VERSION 5.8 ;
BUSBITCHARS "[]" ;
DIVIDERCHAR "/" ;
UNITS
    DATABASE MICRONS 1000 ;
END UNITS

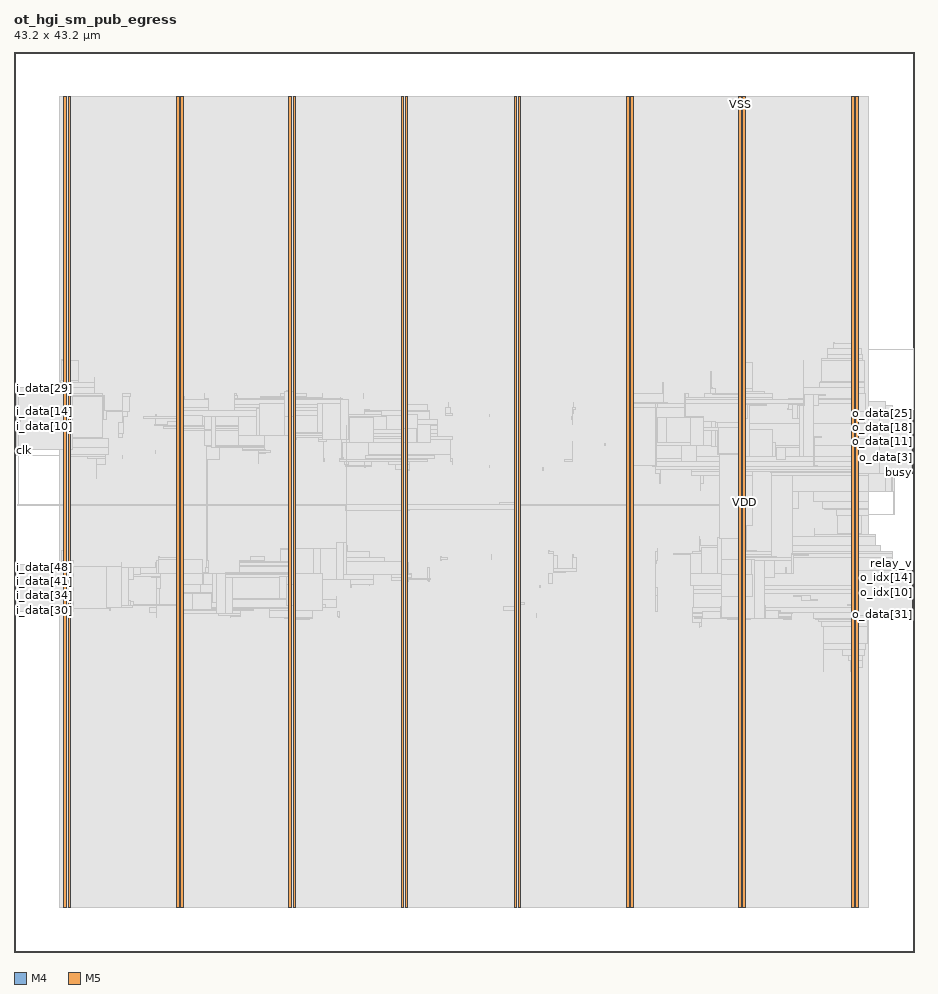
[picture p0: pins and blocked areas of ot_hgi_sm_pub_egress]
MACRO ot_hgi_sm_pub_egress
  FOREIGN ot_hgi_sm_pub_egress 0 0 ;
  CLASS BLOCK ;
  SIZE 43.2 BY 43.2 ;
  PIN busy
    DIRECTION OUTPUT ;
    USE SIGNAL ;
    PORT
      LAYER M4 ;
        RECT  43.116 22.992 43.2 23.016 ;
    END
  END busy
  PIN clk
    DIRECTION INPUT ;
    USE SIGNAL ;
    PORT
      LAYER M4 ;
        RECT  0 24.048 0.084 24.072 ;
    END
  END clk
  PIN i_busy
    DIRECTION INPUT ;
    USE SIGNAL ;
    PORT
      LAYER M4 ;
        RECT  0 24.144 0.084 24.168 ;
    END
  END i_busy
  PIN i_data[0]
    DIRECTION INPUT ;
    USE SIGNAL ;
    PORT
      LAYER M4 ;
        RECT  0 24.24 0.084 24.264 ;
    END
  END i_data[0]
  PIN i_data[10]
    DIRECTION INPUT ;
    USE SIGNAL ;
    PORT
      LAYER M4 ;
        RECT  0 25.2 0.084 25.224 ;
    END
  END i_data[10]
  PIN i_data[11]
    DIRECTION INPUT ;
    USE SIGNAL ;
    PORT
      LAYER M4 ;
        RECT  0 25.296 0.084 25.32 ;
    END
  END i_data[11]
  PIN i_data[12]
    DIRECTION INPUT ;
    USE SIGNAL ;
    PORT
      LAYER M4 ;
        RECT  0 25.392 0.084 25.416 ;
    END
  END i_data[12]
  PIN i_data[13]
    DIRECTION INPUT ;
    USE SIGNAL ;
    PORT
      LAYER M4 ;
        RECT  0 25.488 0.084 25.512 ;
    END
  END i_data[13]
  PIN i_data[14]
    DIRECTION INPUT ;
    USE SIGNAL ;
    PORT
      LAYER M4 ;
        RECT  0 25.584 0.084 25.608 ;
    END
  END i_data[14]
  PIN i_data[15]
    DIRECTION INPUT ;
    USE SIGNAL ;
    PORT
      LAYER M4 ;
        RECT  0 25.68 0.084 25.704 ;
    END
  END i_data[15]
  PIN i_data[16]
    DIRECTION INPUT ;
    USE SIGNAL ;
    PORT
      LAYER M4 ;
        RECT  0 25.776 0.084 25.8 ;
    END
  END i_data[16]
  PIN i_data[17]
    DIRECTION INPUT ;
    USE SIGNAL ;
    PORT
      LAYER M4 ;
        RECT  0 25.872 0.084 25.896 ;
    END
  END i_data[17]
  PIN i_data[18]
    DIRECTION INPUT ;
    USE SIGNAL ;
    PORT
      LAYER M4 ;
        RECT  0 25.968 0.084 25.992 ;
    END
  END i_data[18]
  PIN i_data[19]
    DIRECTION INPUT ;
    USE SIGNAL ;
    PORT
      LAYER M4 ;
        RECT  0 26.064 0.084 26.088 ;
    END
  END i_data[19]
  PIN i_data[1]
    DIRECTION INPUT ;
    USE SIGNAL ;
    PORT
      LAYER M4 ;
        RECT  0 24.336 0.084 24.36 ;
    END
  END i_data[1]
  PIN i_data[20]
    DIRECTION INPUT ;
    USE SIGNAL ;
    PORT
      LAYER M4 ;
        RECT  0 26.16 0.084 26.184 ;
    END
  END i_data[20]
  PIN i_data[21]
    DIRECTION INPUT ;
    USE SIGNAL ;
    PORT
      LAYER M4 ;
        RECT  0 26.256 0.084 26.28 ;
    END
  END i_data[21]
  PIN i_data[22]
    DIRECTION INPUT ;
    USE SIGNAL ;
    PORT
      LAYER M4 ;
        RECT  0 26.352 0.084 26.376 ;
    END
  END i_data[22]
  PIN i_data[23]
    DIRECTION INPUT ;
    USE SIGNAL ;
    PORT
      LAYER M4 ;
        RECT  0 26.448 0.084 26.472 ;
    END
  END i_data[23]
  PIN i_data[24]
    DIRECTION INPUT ;
    USE SIGNAL ;
    PORT
      LAYER M4 ;
        RECT  0 26.544 0.084 26.568 ;
    END
  END i_data[24]
  PIN i_data[25]
    DIRECTION INPUT ;
    USE SIGNAL ;
    PORT
      LAYER M4 ;
        RECT  0 26.64 0.084 26.664 ;
    END
  END i_data[25]
  PIN i_data[26]
    DIRECTION INPUT ;
    USE SIGNAL ;
    PORT
      LAYER M4 ;
        RECT  0 26.736 0.084 26.76 ;
    END
  END i_data[26]
  PIN i_data[27]
    DIRECTION INPUT ;
    USE SIGNAL ;
    PORT
      LAYER M4 ;
        RECT  0 26.832 0.084 26.856 ;
    END
  END i_data[27]
  PIN i_data[28]
    DIRECTION INPUT ;
    USE SIGNAL ;
    PORT
      LAYER M4 ;
        RECT  0 26.928 0.084 26.952 ;
    END
  END i_data[28]
  PIN i_data[29]
    DIRECTION INPUT ;
    USE SIGNAL ;
    PORT
      LAYER M4 ;
        RECT  0 27.024 0.084 27.048 ;
    END
  END i_data[29]
  PIN i_data[2]
    DIRECTION INPUT ;
    USE SIGNAL ;
    PORT
      LAYER M4 ;
        RECT  0 24.432 0.084 24.456 ;
    END
  END i_data[2]
  PIN i_data[30]
    DIRECTION INPUT ;
    USE SIGNAL ;
    PORT
      LAYER M4 ;
        RECT  0 16.368 0.084 16.392 ;
    END
  END i_data[30]
  PIN i_data[31]
    DIRECTION INPUT ;
    USE SIGNAL ;
    PORT
      LAYER M4 ;
        RECT  0 16.464 0.084 16.488 ;
    END
  END i_data[31]
  PIN i_data[32]
    DIRECTION INPUT ;
    USE SIGNAL ;
    PORT
      LAYER M4 ;
        RECT  0 16.56 0.084 16.584 ;
    END
  END i_data[32]
  PIN i_data[33]
    DIRECTION INPUT ;
    USE SIGNAL ;
    PORT
      LAYER M4 ;
        RECT  0 16.656 0.084 16.68 ;
    END
  END i_data[33]
  PIN i_data[34]
    DIRECTION INPUT ;
    USE SIGNAL ;
    PORT
      LAYER M4 ;
        RECT  0 16.752 0.084 16.776 ;
    END
  END i_data[34]
  PIN i_data[35]
    DIRECTION INPUT ;
    USE SIGNAL ;
    PORT
      LAYER M4 ;
        RECT  0 16.848 0.084 16.872 ;
    END
  END i_data[35]
  PIN i_data[36]
    DIRECTION INPUT ;
    USE SIGNAL ;
    PORT
      LAYER M4 ;
        RECT  0 16.944 0.084 16.968 ;
    END
  END i_data[36]
  PIN i_data[37]
    DIRECTION INPUT ;
    USE SIGNAL ;
    PORT
      LAYER M4 ;
        RECT  0 17.04 0.084 17.064 ;
    END
  END i_data[37]
  PIN i_data[38]
    DIRECTION INPUT ;
    USE SIGNAL ;
    PORT
      LAYER M4 ;
        RECT  0 17.136 0.084 17.16 ;
    END
  END i_data[38]
  PIN i_data[39]
    DIRECTION INPUT ;
    USE SIGNAL ;
    PORT
      LAYER M4 ;
        RECT  0 17.232 0.084 17.256 ;
    END
  END i_data[39]
  PIN i_data[3]
    DIRECTION INPUT ;
    USE SIGNAL ;
    PORT
      LAYER M4 ;
        RECT  0 24.528 0.084 24.552 ;
    END
  END i_data[3]
  PIN i_data[40]
    DIRECTION INPUT ;
    USE SIGNAL ;
    PORT
      LAYER M4 ;
        RECT  0 17.328 0.084 17.352 ;
    END
  END i_data[40]
  PIN i_data[41]
    DIRECTION INPUT ;
    USE SIGNAL ;
    PORT
      LAYER M4 ;
        RECT  0 17.424 0.084 17.448 ;
    END
  END i_data[41]
  PIN i_data[42]
    DIRECTION INPUT ;
    USE SIGNAL ;
    PORT
      LAYER M4 ;
        RECT  0 17.52 0.084 17.544 ;
    END
  END i_data[42]
  PIN i_data[43]
    DIRECTION INPUT ;
    USE SIGNAL ;
    PORT
      LAYER M4 ;
        RECT  0 17.616 0.084 17.64 ;
    END
  END i_data[43]
  PIN i_data[44]
    DIRECTION INPUT ;
    USE SIGNAL ;
    PORT
      LAYER M4 ;
        RECT  0 17.712 0.084 17.736 ;
    END
  END i_data[44]
  PIN i_data[45]
    DIRECTION INPUT ;
    USE SIGNAL ;
    PORT
      LAYER M4 ;
        RECT  0 17.808 0.084 17.832 ;
    END
  END i_data[45]
  PIN i_data[46]
    DIRECTION INPUT ;
    USE SIGNAL ;
    PORT
      LAYER M4 ;
        RECT  0 17.904 0.084 17.928 ;
    END
  END i_data[46]
  PIN i_data[47]
    DIRECTION INPUT ;
    USE SIGNAL ;
    PORT
      LAYER M4 ;
        RECT  0 18 0.084 18.024 ;
    END
  END i_data[47]
  PIN i_data[48]
    DIRECTION INPUT ;
    USE SIGNAL ;
    PORT
      LAYER M4 ;
        RECT  0 18.096 0.084 18.12 ;
    END
  END i_data[48]
  PIN i_data[49]
    DIRECTION INPUT ;
    USE SIGNAL ;
    PORT
      LAYER M4 ;
        RECT  0 18.192 0.084 18.216 ;
    END
  END i_data[49]
  PIN i_data[4]
    DIRECTION INPUT ;
    USE SIGNAL ;
    PORT
      LAYER M4 ;
        RECT  0 24.624 0.084 24.648 ;
    END
  END i_data[4]
  PIN i_data[50]
    DIRECTION INPUT ;
    USE SIGNAL ;
    PORT
      LAYER M4 ;
        RECT  0 18.288 0.084 18.312 ;
    END
  END i_data[50]
  PIN i_data[51]
    DIRECTION INPUT ;
    USE SIGNAL ;
    PORT
      LAYER M4 ;
        RECT  0 18.384 0.084 18.408 ;
    END
  END i_data[51]
  PIN i_data[5]
    DIRECTION INPUT ;
    USE SIGNAL ;
    PORT
      LAYER M4 ;
        RECT  0 24.72 0.084 24.744 ;
    END
  END i_data[5]
  PIN i_data[6]
    DIRECTION INPUT ;
    USE SIGNAL ;
    PORT
      LAYER M4 ;
        RECT  0 24.816 0.084 24.84 ;
    END
  END i_data[6]
  PIN i_data[7]
    DIRECTION INPUT ;
    USE SIGNAL ;
    PORT
      LAYER M4 ;
        RECT  0 24.912 0.084 24.936 ;
    END
  END i_data[7]
  PIN i_data[8]
    DIRECTION INPUT ;
    USE SIGNAL ;
    PORT
      LAYER M4 ;
        RECT  0 25.008 0.084 25.032 ;
    END
  END i_data[8]
  PIN i_data[9]
    DIRECTION INPUT ;
    USE SIGNAL ;
    PORT
      LAYER M4 ;
        RECT  0 25.104 0.084 25.128 ;
    END
  END i_data[9]
  PIN i_v
    DIRECTION INPUT ;
    USE SIGNAL ;
    PORT
      LAYER M4 ;
        RECT  0 18.48 0.084 18.504 ;
    END
  END i_v
  PIN o_data[0]
    DIRECTION OUTPUT ;
    USE SIGNAL ;
    PORT
      LAYER M4 ;
        RECT  43.116 23.088 43.2 23.112 ;
    END
  END o_data[0]
  PIN o_data[10]
    DIRECTION OUTPUT ;
    USE SIGNAL ;
    PORT
      LAYER M4 ;
        RECT  43.116 24.048 43.2 24.072 ;
    END
  END o_data[10]
  PIN o_data[11]
    DIRECTION OUTPUT ;
    USE SIGNAL ;
    PORT
      LAYER M4 ;
        RECT  43.116 24.144 43.2 24.168 ;
    END
  END o_data[11]
  PIN o_data[12]
    DIRECTION OUTPUT ;
    USE SIGNAL ;
    PORT
      LAYER M4 ;
        RECT  43.116 24.24 43.2 24.264 ;
    END
  END o_data[12]
  PIN o_data[13]
    DIRECTION OUTPUT ;
    USE SIGNAL ;
    PORT
      LAYER M4 ;
        RECT  43.116 24.336 43.2 24.36 ;
    END
  END o_data[13]
  PIN o_data[14]
    DIRECTION OUTPUT ;
    USE SIGNAL ;
    PORT
      LAYER M4 ;
        RECT  43.116 24.432 43.2 24.456 ;
    END
  END o_data[14]
  PIN o_data[15]
    DIRECTION OUTPUT ;
    USE SIGNAL ;
    PORT
      LAYER M4 ;
        RECT  43.116 24.528 43.2 24.552 ;
    END
  END o_data[15]
  PIN o_data[16]
    DIRECTION OUTPUT ;
    USE SIGNAL ;
    PORT
      LAYER M4 ;
        RECT  43.116 24.624 43.2 24.648 ;
    END
  END o_data[16]
  PIN o_data[17]
    DIRECTION OUTPUT ;
    USE SIGNAL ;
    PORT
      LAYER M4 ;
        RECT  43.116 24.72 43.2 24.744 ;
    END
  END o_data[17]
  PIN o_data[18]
    DIRECTION OUTPUT ;
    USE SIGNAL ;
    PORT
      LAYER M4 ;
        RECT  43.116 24.816 43.2 24.84 ;
    END
  END o_data[18]
  PIN o_data[19]
    DIRECTION OUTPUT ;
    USE SIGNAL ;
    PORT
      LAYER M4 ;
        RECT  43.116 24.912 43.2 24.936 ;
    END
  END o_data[19]
  PIN o_data[1]
    DIRECTION OUTPUT ;
    USE SIGNAL ;
    PORT
      LAYER M4 ;
        RECT  43.116 23.184 43.2 23.208 ;
    END
  END o_data[1]
  PIN o_data[20]
    DIRECTION OUTPUT ;
    USE SIGNAL ;
    PORT
      LAYER M4 ;
        RECT  43.116 25.008 43.2 25.032 ;
    END
  END o_data[20]
  PIN o_data[21]
    DIRECTION OUTPUT ;
    USE SIGNAL ;
    PORT
      LAYER M4 ;
        RECT  43.116 25.104 43.2 25.128 ;
    END
  END o_data[21]
  PIN o_data[22]
    DIRECTION OUTPUT ;
    USE SIGNAL ;
    PORT
      LAYER M4 ;
        RECT  43.116 25.2 43.2 25.224 ;
    END
  END o_data[22]
  PIN o_data[23]
    DIRECTION OUTPUT ;
    USE SIGNAL ;
    PORT
      LAYER M4 ;
        RECT  43.116 25.296 43.2 25.32 ;
    END
  END o_data[23]
  PIN o_data[24]
    DIRECTION OUTPUT ;
    USE SIGNAL ;
    PORT
      LAYER M4 ;
        RECT  43.116 25.392 43.2 25.416 ;
    END
  END o_data[24]
  PIN o_data[25]
    DIRECTION OUTPUT ;
    USE SIGNAL ;
    PORT
      LAYER M4 ;
        RECT  43.116 25.488 43.2 25.512 ;
    END
  END o_data[25]
  PIN o_data[26]
    DIRECTION OUTPUT ;
    USE SIGNAL ;
    PORT
      LAYER M4 ;
        RECT  43.116 25.584 43.2 25.608 ;
    END
  END o_data[26]
  PIN o_data[27]
    DIRECTION OUTPUT ;
    USE SIGNAL ;
    PORT
      LAYER M4 ;
        RECT  43.116 25.68 43.2 25.704 ;
    END
  END o_data[27]
  PIN o_data[28]
    DIRECTION OUTPUT ;
    USE SIGNAL ;
    PORT
      LAYER M4 ;
        RECT  43.116 25.776 43.2 25.8 ;
    END
  END o_data[28]
  PIN o_data[29]
    DIRECTION OUTPUT ;
    USE SIGNAL ;
    PORT
      LAYER M4 ;
        RECT  43.116 25.872 43.2 25.896 ;
    END
  END o_data[29]
  PIN o_data[2]
    DIRECTION OUTPUT ;
    USE SIGNAL ;
    PORT
      LAYER M4 ;
        RECT  43.116 23.28 43.2 23.304 ;
    END
  END o_data[2]
  PIN o_data[30]
    DIRECTION OUTPUT ;
    USE SIGNAL ;
    PORT
      LAYER M4 ;
        RECT  43.116 25.968 43.2 25.992 ;
    END
  END o_data[30]
  PIN o_data[31]
    DIRECTION OUTPUT ;
    USE SIGNAL ;
    PORT
      LAYER M4 ;
        RECT  43.116 16.176 43.2 16.2 ;
    END
  END o_data[31]
  PIN o_data[3]
    DIRECTION OUTPUT ;
    USE SIGNAL ;
    PORT
      LAYER M4 ;
        RECT  43.116 23.376 43.2 23.4 ;
    END
  END o_data[3]
  PIN o_data[4]
    DIRECTION OUTPUT ;
    USE SIGNAL ;
    PORT
      LAYER M4 ;
        RECT  43.116 23.472 43.2 23.496 ;
    END
  END o_data[4]
  PIN o_data[5]
    DIRECTION OUTPUT ;
    USE SIGNAL ;
    PORT
      LAYER M4 ;
        RECT  43.116 23.568 43.2 23.592 ;
    END
  END o_data[5]
  PIN o_data[6]
    DIRECTION OUTPUT ;
    USE SIGNAL ;
    PORT
      LAYER M4 ;
        RECT  43.116 23.664 43.2 23.688 ;
    END
  END o_data[6]
  PIN o_data[7]
    DIRECTION OUTPUT ;
    USE SIGNAL ;
    PORT
      LAYER M4 ;
        RECT  43.116 23.76 43.2 23.784 ;
    END
  END o_data[7]
  PIN o_data[8]
    DIRECTION OUTPUT ;
    USE SIGNAL ;
    PORT
      LAYER M4 ;
        RECT  43.116 23.856 43.2 23.88 ;
    END
  END o_data[8]
  PIN o_data[9]
    DIRECTION OUTPUT ;
    USE SIGNAL ;
    PORT
      LAYER M4 ;
        RECT  43.116 23.952 43.2 23.976 ;
    END
  END o_data[9]
  PIN o_idx[0]
    DIRECTION OUTPUT ;
    USE SIGNAL ;
    PORT
      LAYER M4 ;
        RECT  43.116 16.272 43.2 16.296 ;
    END
  END o_idx[0]
  PIN o_idx[10]
    DIRECTION OUTPUT ;
    USE SIGNAL ;
    PORT
      LAYER M4 ;
        RECT  43.116 17.232 43.2 17.256 ;
    END
  END o_idx[10]
  PIN o_idx[11]
    DIRECTION OUTPUT ;
    USE SIGNAL ;
    PORT
      LAYER M4 ;
        RECT  43.116 17.328 43.2 17.352 ;
    END
  END o_idx[11]
  PIN o_idx[12]
    DIRECTION OUTPUT ;
    USE SIGNAL ;
    PORT
      LAYER M4 ;
        RECT  43.116 17.424 43.2 17.448 ;
    END
  END o_idx[12]
  PIN o_idx[13]
    DIRECTION OUTPUT ;
    USE SIGNAL ;
    PORT
      LAYER M4 ;
        RECT  43.116 17.52 43.2 17.544 ;
    END
  END o_idx[13]
  PIN o_idx[14]
    DIRECTION OUTPUT ;
    USE SIGNAL ;
    PORT
      LAYER M4 ;
        RECT  43.116 17.616 43.2 17.64 ;
    END
  END o_idx[14]
  PIN o_idx[15]
    DIRECTION OUTPUT ;
    USE SIGNAL ;
    PORT
      LAYER M4 ;
        RECT  43.116 17.712 43.2 17.736 ;
    END
  END o_idx[15]
  PIN o_idx[16]
    DIRECTION OUTPUT ;
    USE SIGNAL ;
    PORT
      LAYER M4 ;
        RECT  43.116 17.808 43.2 17.832 ;
    END
  END o_idx[16]
  PIN o_idx[17]
    DIRECTION OUTPUT ;
    USE SIGNAL ;
    PORT
      LAYER M4 ;
        RECT  43.116 17.904 43.2 17.928 ;
    END
  END o_idx[17]
  PIN o_idx[18]
    DIRECTION OUTPUT ;
    USE SIGNAL ;
    PORT
      LAYER M4 ;
        RECT  43.116 18 43.2 18.024 ;
    END
  END o_idx[18]
  PIN o_idx[19]
    DIRECTION OUTPUT ;
    USE SIGNAL ;
    PORT
      LAYER M4 ;
        RECT  43.116 18.096 43.2 18.12 ;
    END
  END o_idx[19]
  PIN o_idx[1]
    DIRECTION OUTPUT ;
    USE SIGNAL ;
    PORT
      LAYER M4 ;
        RECT  43.116 16.368 43.2 16.392 ;
    END
  END o_idx[1]
  PIN o_idx[2]
    DIRECTION OUTPUT ;
    USE SIGNAL ;
    PORT
      LAYER M4 ;
        RECT  43.116 16.464 43.2 16.488 ;
    END
  END o_idx[2]
  PIN o_idx[3]
    DIRECTION OUTPUT ;
    USE SIGNAL ;
    PORT
      LAYER M4 ;
        RECT  43.116 16.56 43.2 16.584 ;
    END
  END o_idx[3]
  PIN o_idx[4]
    DIRECTION OUTPUT ;
    USE SIGNAL ;
    PORT
      LAYER M4 ;
        RECT  43.116 16.656 43.2 16.68 ;
    END
  END o_idx[4]
  PIN o_idx[5]
    DIRECTION OUTPUT ;
    USE SIGNAL ;
    PORT
      LAYER M4 ;
        RECT  43.116 16.752 43.2 16.776 ;
    END
  END o_idx[5]
  PIN o_idx[6]
    DIRECTION OUTPUT ;
    USE SIGNAL ;
    PORT
      LAYER M4 ;
        RECT  43.116 16.848 43.2 16.872 ;
    END
  END o_idx[6]
  PIN o_idx[7]
    DIRECTION OUTPUT ;
    USE SIGNAL ;
    PORT
      LAYER M4 ;
        RECT  43.116 16.944 43.2 16.968 ;
    END
  END o_idx[7]
  PIN o_idx[8]
    DIRECTION OUTPUT ;
    USE SIGNAL ;
    PORT
      LAYER M4 ;
        RECT  43.116 17.04 43.2 17.064 ;
    END
  END o_idx[8]
  PIN o_idx[9]
    DIRECTION OUTPUT ;
    USE SIGNAL ;
    PORT
      LAYER M4 ;
        RECT  43.116 17.136 43.2 17.16 ;
    END
  END o_idx[9]
  PIN o_v
    DIRECTION OUTPUT ;
    USE SIGNAL ;
    PORT
      LAYER M4 ;
        RECT  43.116 18.192 43.2 18.216 ;
    END
  END o_v
  PIN relay_v
    DIRECTION OUTPUT ;
    USE SIGNAL ;
    PORT
      LAYER M4 ;
        RECT  43.116 18.288 43.2 18.312 ;
    END
  END relay_v
  PIN rn
    DIRECTION INPUT ;
    USE SIGNAL ;
    PORT
      LAYER M4 ;
        RECT  0 18.576 0.084 18.6 ;
    END
  END rn
  PIN VDD
    DIRECTION INOUT ;
    USE POWER ;
    PORT
      LAYER M5 ;
        RECT  40.392 2.151 40.512 41.049 ;
        RECT  34.992 2.151 35.112 41.049 ;
        RECT  29.592 2.151 29.712 41.049 ;
        RECT  24.192 2.151 24.312 41.049 ;
        RECT  18.792 2.151 18.912 41.049 ;
        RECT  13.392 2.151 13.512 41.049 ;
        RECT  7.992 2.151 8.112 41.049 ;
        RECT  2.592 2.151 2.712 41.049 ;
    END
  END VDD
  PIN VSS
    DIRECTION INOUT ;
    USE GROUND ;
    PORT
      LAYER M5 ;
        RECT  40.2 2.137 40.32 41.063 ;
        RECT  34.8 2.137 34.92 41.063 ;
        RECT  29.4 2.137 29.52 41.063 ;
        RECT  24 2.137 24.12 41.063 ;
        RECT  18.6 2.137 18.72 41.063 ;
        RECT  13.2 2.137 13.32 41.063 ;
        RECT  7.8 2.137 7.92 41.063 ;
        RECT  2.4 2.137 2.52 41.063 ;
    END
  END VSS
  # OT_OBS_CLOSED layer=M5 d_um=1.536 added=6
  OBS
    LAYER RVTN ;
     RECT  2.16 2.16 41.04 2.295 ;
     RECT  2.16 2.565 41.04 2.835 ;
     RECT  2.16 3.105 41.04 3.375 ;
     RECT  2.16 3.645 41.04 3.915 ;
     RECT  2.16 4.185 41.04 4.455 ;
     RECT  2.16 4.725 41.04 4.995 ;
     RECT  2.16 5.265 41.04 5.535 ;
     RECT  2.16 5.805 41.04 6.075 ;
     RECT  2.16 6.345 41.04 6.615 ;
     RECT  2.16 6.885 41.04 7.155 ;
     RECT  2.16 7.425 41.04 7.695 ;
     RECT  2.16 7.965 41.04 8.235 ;
     RECT  2.16 8.505 41.04 8.775 ;
     RECT  2.16 9.045 41.04 9.315 ;
     RECT  2.16 9.585 41.04 9.855 ;
     RECT  2.16 10.125 41.04 10.395 ;
     RECT  2.16 10.665 41.04 10.935 ;
     RECT  2.16 11.205 41.04 11.475 ;
     RECT  2.16 11.745 41.04 12.015 ;
     RECT  2.16 12.285 41.04 12.555 ;
     RECT  2.16 12.825 41.04 13.095 ;
     RECT  2.16 13.365 41.04 13.635 ;
     RECT  2.16 13.905 41.04 14.175 ;
     RECT  2.16 14.445 41.04 14.715 ;
     RECT  2.16 14.985 41.04 15.255 ;
     RECT  2.16 15.525 41.04 15.795 ;
     RECT  2.16 16.065 41.04 16.335 ;
     RECT  2.16 16.605 41.04 16.875 ;
     RECT  2.16 17.145 41.04 17.415 ;
     RECT  2.16 17.685 41.04 17.955 ;
     RECT  2.16 18.225 41.04 18.495 ;
     RECT  2.16 18.765 41.04 19.035 ;
     RECT  2.16 19.305 41.04 19.575 ;
     RECT  2.16 19.845 41.04 20.115 ;
     RECT  2.16 20.385 41.04 20.655 ;
     RECT  2.16 20.925 41.04 21.195 ;
     RECT  2.16 21.465 41.04 21.735 ;
     RECT  2.16 22.005 41.04 22.275 ;
     RECT  2.16 22.545 41.04 22.815 ;
     RECT  2.16 23.085 41.04 23.355 ;
     RECT  2.16 23.625 41.04 23.895 ;
     RECT  2.16 24.165 41.04 24.435 ;
     RECT  2.16 24.705 41.04 24.975 ;
     RECT  2.16 25.245 41.04 25.515 ;
     RECT  2.16 25.785 41.04 26.055 ;
     RECT  2.16 26.325 41.04 26.595 ;
     RECT  2.16 26.865 41.04 27.135 ;
     RECT  2.16 27.405 41.04 27.675 ;
     RECT  2.16 27.945 41.04 28.215 ;
     RECT  2.16 28.485 41.04 28.755 ;
     RECT  2.16 29.025 41.04 29.295 ;
     RECT  2.16 29.565 41.04 29.835 ;
     RECT  2.16 30.105 41.04 30.375 ;
     RECT  2.16 30.645 41.04 30.915 ;
     RECT  2.16 31.185 41.04 31.455 ;
     RECT  2.16 31.725 41.04 31.995 ;
     RECT  2.16 32.265 41.04 32.535 ;
     RECT  2.16 32.805 41.04 33.075 ;
     RECT  2.16 33.345 41.04 33.615 ;
     RECT  2.16 33.885 41.04 34.155 ;
     RECT  2.16 34.425 41.04 34.695 ;
     RECT  2.16 34.965 41.04 35.235 ;
     RECT  2.16 35.505 41.04 35.775 ;
     RECT  2.16 36.045 41.04 36.315 ;
     RECT  2.16 36.585 41.04 36.855 ;
     RECT  2.16 37.125 41.04 37.395 ;
     RECT  2.16 37.665 41.04 37.935 ;
     RECT  2.16 38.205 41.04 38.475 ;
     RECT  2.16 38.745 41.04 39.015 ;
     RECT  2.16 39.285 41.04 39.555 ;
     RECT  2.16 39.825 41.04 40.095 ;
     RECT  2.16 40.365 41.04 40.635 ;
     RECT  2.16 40.905 41.04 41.04 ;
    LAYER RVTP ;
     RECT  2.16 2.295 41.04 2.565 ;
     RECT  2.16 2.835 41.04 3.105 ;
     RECT  2.16 3.375 41.04 3.645 ;
     RECT  2.16 3.915 41.04 4.185 ;
     RECT  2.16 4.455 41.04 4.725 ;
     RECT  2.16 4.995 41.04 5.265 ;
     RECT  2.16 5.535 41.04 5.805 ;
     RECT  2.16 6.075 41.04 6.345 ;
     RECT  2.16 6.615 41.04 6.885 ;
     RECT  2.16 7.155 41.04 7.425 ;
     RECT  2.16 7.695 41.04 7.965 ;
     RECT  2.16 8.235 41.04 8.505 ;
     RECT  2.16 8.775 41.04 9.045 ;
     RECT  2.16 9.315 41.04 9.585 ;
     RECT  2.16 9.855 41.04 10.125 ;
     RECT  2.16 10.395 41.04 10.665 ;
     RECT  2.16 10.935 41.04 11.205 ;
     RECT  2.16 11.475 41.04 11.745 ;
     RECT  2.16 12.015 41.04 12.285 ;
     RECT  2.16 12.555 41.04 12.825 ;
     RECT  2.16 13.095 41.04 13.365 ;
     RECT  2.16 13.635 41.04 13.905 ;
     RECT  2.16 14.175 41.04 14.445 ;
     RECT  2.16 14.715 41.04 14.985 ;
     RECT  2.16 15.255 41.04 15.525 ;
     RECT  2.16 15.795 41.04 16.065 ;
     RECT  2.16 16.335 41.04 16.605 ;
     RECT  2.16 16.875 41.04 17.145 ;
     RECT  2.16 17.415 41.04 17.685 ;
     RECT  2.16 17.955 41.04 18.225 ;
     RECT  2.16 18.495 41.04 18.765 ;
     RECT  2.16 19.035 41.04 19.305 ;
     RECT  2.16 19.575 41.04 19.845 ;
     RECT  2.16 20.115 41.04 20.385 ;
     RECT  2.16 20.655 41.04 20.925 ;
     RECT  2.16 21.195 41.04 21.465 ;
     RECT  2.16 21.735 41.04 22.005 ;
     RECT  2.16 22.275 41.04 22.545 ;
     RECT  2.16 22.815 41.04 23.085 ;
     RECT  2.16 23.355 41.04 23.625 ;
     RECT  2.16 23.895 41.04 24.165 ;
     RECT  2.16 24.435 41.04 24.705 ;
     RECT  2.16 24.975 41.04 25.245 ;
     RECT  2.16 25.515 41.04 25.785 ;
     RECT  2.16 26.055 41.04 26.325 ;
     RECT  2.16 26.595 41.04 26.865 ;
     RECT  2.16 27.135 41.04 27.405 ;
     RECT  2.16 27.675 41.04 27.945 ;
     RECT  2.16 28.215 41.04 28.485 ;
     RECT  2.16 28.755 41.04 29.025 ;
     RECT  2.16 29.295 41.04 29.565 ;
     RECT  2.16 29.835 41.04 30.105 ;
     RECT  2.16 30.375 41.04 30.645 ;
     RECT  2.16 30.915 41.04 31.185 ;
     RECT  2.16 31.455 41.04 31.725 ;
     RECT  2.16 31.995 41.04 32.265 ;
     RECT  2.16 32.535 41.04 32.805 ;
     RECT  2.16 33.075 41.04 33.345 ;
     RECT  2.16 33.615 41.04 33.885 ;
     RECT  2.16 34.155 41.04 34.425 ;
     RECT  2.16 34.695 41.04 34.965 ;
     RECT  2.16 35.235 41.04 35.505 ;
     RECT  2.16 35.775 41.04 36.045 ;
     RECT  2.16 36.315 41.04 36.585 ;
     RECT  2.16 36.855 41.04 37.125 ;
     RECT  2.16 37.395 41.04 37.665 ;
     RECT  2.16 37.935 41.04 38.205 ;
     RECT  2.16 38.475 41.04 38.745 ;
     RECT  2.16 39.015 41.04 39.285 ;
     RECT  2.16 39.555 41.04 39.825 ;
     RECT  2.16 40.095 41.04 40.365 ;
     RECT  2.16 40.635 41.04 40.905 ;
    LAYER M1 ;
     RECT  2.16 2.151 41.04 41.049 ;
    LAYER M2 ;
     RECT  0.103 16.848 0.203 17.1 ;
     RECT  0.103 18.198 0.203 18.216 ;
     RECT  0.103 25.02 0.535 25.038 ;
     RECT  0.535 17.46 2.16 17.478 ;
     RECT  0.103 23.832 2.16 23.85 ;
     RECT  0.535 25.02 2.16 25.074 ;
     RECT  2.16 2.151 41.04 41.049 ;
     RECT  41.04 16.146 41.351 20.034 ;
     RECT  41.351 16.146 41.603 19.494 ;
     RECT  41.04 22.086 41.855 26.424 ;
     RECT  41.603 16.146 42.107 19.224 ;
     RECT  42.107 16.146 42.143 18.414 ;
     RECT  41.855 22.086 42.143 26.244 ;
     RECT  42.143 16.146 42.179 17.604 ;
     RECT  42.107 19.206 42.179 19.224 ;
     RECT  42.143 22.086 42.179 25.2 ;
     RECT  42.143 26.226 42.179 26.244 ;
     RECT  42.179 16.416 42.215 16.974 ;
     RECT  42.179 22.716 42.215 23.922 ;
     RECT  41.04 21.006 42.251 21.024 ;
     RECT  42.215 16.506 43.115 16.524 ;
     RECT  42.215 23.166 43.115 23.922 ;
     RECT  41.04 28.926 43.187 28.944 ;
    LAYER M3 ;
     RECT  2.415 2.143 2.505 2.413 ;
     RECT  7.815 2.143 7.905 2.413 ;
     RECT  13.215 2.143 13.305 2.413 ;
     RECT  18.615 2.143 18.705 2.413 ;
     RECT  24.015 2.143 24.105 2.413 ;
     RECT  29.415 2.143 29.505 2.413 ;
     RECT  34.815 2.143 34.905 2.413 ;
     RECT  40.215 2.143 40.305 2.413 ;
     RECT  40.215 2.413 40.497 13.441 ;
     RECT  40.14 13.441 40.497 13.639 ;
     RECT  40.14 13.639 40.734 13.981 ;
     RECT  40.068 13.981 40.734 14.215 ;
     RECT  38.844 13.441 38.862 14.521 ;
     RECT  39.744 14.215 40.842 14.521 ;
     RECT  38.844 14.521 40.878 14.791 ;
     RECT  32.904 15.565 32.922 15.601 ;
     RECT  38.844 14.791 40.95 15.601 ;
     RECT  32.904 15.601 32.994 15.835 ;
     RECT  38.772 15.601 40.95 15.871 ;
     RECT  13.215 2.413 13.497 15.961 ;
     RECT  34.815 2.413 35.097 15.961 ;
     RECT  38.628 15.871 40.95 15.961 ;
     RECT  13.176 15.961 14.166 15.997 ;
     RECT  34.272 15.961 35.334 15.997 ;
     RECT  36.936 15.961 37.314 15.997 ;
     RECT  38.484 15.961 40.95 15.997 ;
     RECT  12.996 15.997 14.346 16.069 ;
     RECT  33.948 15.997 35.334 16.069 ;
     RECT  36.648 15.997 37.314 16.069 ;
     RECT  10.368 16.069 10.386 16.105 ;
     RECT  15.588 16.069 15.606 16.105 ;
     RECT  32.58 15.835 32.994 16.105 ;
     RECT  33.948 16.069 37.314 16.105 ;
     RECT  10.368 16.105 10.854 16.141 ;
     RECT  9.828 16.141 10.854 16.231 ;
     RECT  25.056 16.069 25.074 16.259 ;
     RECT  7.815 2.413 8.097 16.267 ;
     RECT  8.964 16.231 10.854 16.267 ;
     RECT  32.58 16.105 37.314 16.267 ;
     RECT  6.84 16.069 6.858 16.303 ;
     RECT  32.58 16.267 37.386 16.303 ;
     RECT  38.376 15.997 40.95 16.303 ;
     RECT  2.415 2.413 2.697 16.363 ;
     RECT  15.516 16.105 15.606 16.367 ;
     RECT  42.156 16.141 42.174 16.396 ;
     RECT  12.276 16.069 14.346 16.405 ;
     RECT  7.815 16.267 10.854 16.411 ;
     RECT  12.276 16.405 14.598 16.411 ;
     RECT  24.015 2.413 24.297 16.411 ;
     RECT  7.815 16.411 11.502 16.439 ;
     RECT  9.504 16.439 11.502 16.501 ;
     RECT  12.276 16.411 14.778 16.501 ;
     RECT  4.608 16.411 4.626 16.507 ;
     RECT  6.48 16.303 6.858 16.529 ;
     RECT  32.58 16.303 40.95 16.529 ;
     RECT  9.504 16.501 14.778 16.537 ;
     RECT  4.392 16.507 4.626 16.555 ;
     RECT  5.688 16.537 5.706 16.555 ;
     RECT  23.472 16.411 24.297 16.565 ;
     RECT  6.84 16.529 6.858 16.651 ;
     RECT  24.015 16.565 24.297 16.681 ;
     RECT  43.092 16.501 43.11 16.781 ;
     RECT  0.108 16.747 0.126 16.795 ;
     RECT  24.015 16.681 24.498 16.799 ;
     RECT  4.392 16.555 5.706 16.829 ;
     RECT  4.392 16.829 5.562 16.88 ;
     RECT  9.504 16.537 15.498 16.943 ;
     RECT  4.392 16.88 5.49 16.973 ;
     RECT  15.48 16.943 15.498 17.069 ;
     RECT  30.78 16.339 30.87 17.113 ;
     RECT  4.392 16.973 5.202 17.131 ;
     RECT  42.156 16.396 42.21 17.131 ;
     RECT  7.815 16.439 8.586 17.185 ;
     RECT  9.504 16.943 14.67 17.185 ;
     RECT  32.616 16.529 40.95 17.221 ;
     RECT  7.815 17.185 14.67 17.249 ;
     RECT  0.108 16.795 0.198 17.261 ;
     RECT  42.12 17.131 42.21 17.261 ;
     RECT  2.415 16.363 2.862 17.311 ;
     RECT  32.616 17.221 41.058 17.419 ;
     RECT  42.12 17.261 42.174 17.419 ;
     RECT  6.84 16.651 6.966 17.455 ;
     RECT  30.78 17.113 30.906 17.483 ;
     RECT  2.304 17.311 2.862 17.581 ;
     RECT  32.616 17.419 42.174 17.581 ;
     RECT  25.236 17.491 25.254 17.609 ;
     RECT  16.128 17.491 16.218 17.617 ;
     RECT  17.064 17.581 17.082 17.617 ;
     RECT  2.304 17.581 3.114 17.681 ;
     RECT  3.996 17.131 5.202 17.681 ;
     RECT  8.928 17.249 14.67 17.707 ;
     RECT  3.996 17.681 4.59 17.725 ;
     RECT  18.615 2.413 18.897 17.761 ;
     RECT  2.304 17.681 2.862 17.803 ;
     RECT  18.615 17.761 18.954 17.851 ;
     RECT  19.908 17.761 19.926 17.851 ;
     RECT  3.78 17.725 4.59 17.879 ;
     RECT  8.928 17.707 14.706 17.887 ;
     RECT  8.928 17.887 15.246 17.899 ;
     RECT  16.128 17.617 17.262 17.899 ;
     RECT  19.836 17.851 19.926 17.899 ;
     RECT  2.268 17.803 2.862 17.915 ;
     RECT  0.54 17.455 0.558 17.933 ;
     RECT  19.836 17.899 19.998 17.951 ;
     RECT  6.84 17.455 7.038 17.959 ;
     RECT  18.144 17.851 18.954 17.995 ;
     RECT  5.544 17.899 5.706 18.031 ;
     RECT  6.588 17.959 7.038 18.031 ;
     RECT  4.176 17.879 4.59 18.059 ;
     RECT  8.928 17.899 17.262 18.139 ;
     RECT  18.144 17.995 19.062 18.139 ;
     RECT  4.5 18.059 4.59 18.149 ;
     RECT  8.928 18.139 19.062 18.149 ;
     RECT  5.544 18.031 7.038 18.157 ;
     RECT  7.815 17.249 8.097 18.157 ;
     RECT  8.928 18.149 9.342 18.173 ;
     RECT  2.268 17.915 2.697 18.185 ;
     RECT  4.572 18.149 4.59 18.185 ;
     RECT  10.08 18.149 18.954 18.185 ;
     RECT  25.632 17.689 25.83 18.185 ;
     RECT  9.036 18.173 9.342 18.221 ;
     RECT  10.152 18.185 18.954 18.221 ;
     RECT  25.884 18.193 26.478 18.265 ;
     RECT  5.544 18.157 8.097 18.301 ;
     RECT  0.108 18.193 0.198 18.413 ;
     RECT  5.544 18.301 8.262 18.419 ;
     RECT  25.884 18.265 26.982 18.419 ;
     RECT  5.544 18.419 5.562 18.455 ;
     RECT  6.408 18.419 8.262 18.455 ;
     RECT  9.216 18.221 9.342 18.455 ;
     RECT  19.836 17.951 19.926 18.455 ;
     RECT  0.18 18.413 0.198 18.461 ;
     RECT  6.804 18.455 8.262 18.527 ;
     RECT  10.836 18.221 18.954 18.527 ;
     RECT  10.836 18.527 15.138 18.563 ;
     RECT  2.304 18.185 2.697 18.661 ;
     RECT  30.78 17.483 30.798 18.661 ;
     RECT  5.148 18.475 5.166 18.689 ;
     RECT  6.804 18.527 8.19 18.689 ;
     RECT  10.836 18.563 14.382 18.689 ;
     RECT  15.12 18.563 15.138 18.689 ;
     RECT  15.912 18.527 18.954 18.689 ;
     RECT  6.84 18.689 8.19 18.725 ;
     RECT  10.836 18.689 14.202 18.725 ;
     RECT  12.78 18.725 14.058 18.749 ;
     RECT  15.912 18.689 18.897 18.749 ;
     RECT  2.304 18.661 2.862 18.797 ;
     RECT  9.252 18.455 9.342 18.797 ;
     RECT  10.836 18.725 12.006 18.797 ;
     RECT  6.84 18.725 8.097 18.803 ;
     RECT  30.78 18.661 30.834 18.805 ;
     RECT  20.484 18.769 20.502 18.841 ;
     RECT  6.948 18.803 8.097 18.959 ;
     RECT  15.912 18.749 17.802 18.959 ;
     RECT  20.484 18.841 20.79 18.959 ;
     RECT  26.82 18.419 26.982 18.959 ;
     RECT  32.472 17.581 42.174 18.959 ;
     RECT  6.948 18.959 6.966 18.995 ;
     RECT  11.376 18.797 12.006 18.995 ;
     RECT  20.484 18.959 20.502 18.995 ;
     RECT  32.472 18.959 36.594 18.995 ;
     RECT  25.884 18.419 26.082 19.031 ;
     RECT  22.896 18.841 22.914 19.067 ;
     RECT  26.82 18.959 26.838 19.067 ;
     RECT  32.472 18.995 36.378 19.103 ;
     RECT  25.884 19.031 25.902 19.111 ;
     RECT  31.644 19.099 31.662 19.139 ;
     RECT  37.332 18.959 42.174 19.139 ;
     RECT  15.912 18.959 17.046 19.229 ;
     RECT  25.668 19.111 25.902 19.229 ;
     RECT  30.78 18.805 30.906 19.229 ;
     RECT  32.58 19.103 36.378 19.229 ;
     RECT  37.368 19.139 42.174 19.229 ;
     RECT  2.304 18.797 2.697 19.265 ;
     RECT  25.668 19.229 25.686 19.265 ;
     RECT  32.904 19.229 35.622 19.265 ;
     RECT  15.912 19.229 16.002 19.339 ;
     RECT  12.78 18.749 13.497 19.373 ;
     RECT  30.888 19.229 30.906 19.373 ;
     RECT  15.48 19.339 16.002 19.499 ;
     RECT  37.368 19.229 41.598 19.499 ;
     RECT  32.904 19.265 35.154 19.535 ;
     RECT  15.48 19.499 15.498 19.661 ;
     RECT  32.904 19.535 32.958 19.805 ;
     RECT  33.768 19.535 35.154 19.901 ;
     RECT  32.904 19.805 32.922 19.949 ;
     RECT  37.368 19.499 41.346 19.949 ;
     RECT  38.412 19.949 41.346 20.039 ;
     RECT  33.876 19.901 35.154 20.075 ;
     RECT  39.528 20.039 40.698 20.075 ;
     RECT  38.412 20.039 38.43 20.309 ;
     RECT  34.092 20.075 35.154 20.461 ;
     RECT  39.528 20.075 40.662 20.965 ;
     RECT  18.615 18.749 18.897 21.199 ;
     RECT  39.456 20.965 41.022 21.235 ;
     RECT  24.015 16.799 24.297 21.259 ;
     RECT  37.368 19.949 37.386 21.271 ;
     RECT  38.88 21.235 41.022 21.271 ;
     RECT  18.615 21.199 18.99 21.293 ;
     RECT  23.328 21.259 24.297 21.451 ;
     RECT  22.752 21.451 24.297 21.497 ;
     RECT  23.328 21.497 24.297 21.569 ;
     RECT  38.808 21.271 41.022 21.631 ;
     RECT  37.368 21.271 37.638 22.081 ;
     RECT  38.376 21.631 41.022 22.081 ;
     RECT  42.228 21.001 42.246 22.081 ;
     RECT  32.94 22.171 32.958 22.477 ;
     RECT  32.94 22.477 33.102 22.855 ;
     RECT  34.092 20.461 35.442 22.855 ;
     RECT  36.36 19.229 36.378 22.855 ;
     RECT  37.368 22.081 41.022 22.855 ;
     RECT  32.544 22.855 33.102 22.891 ;
     RECT  33.84 22.855 35.442 22.891 ;
     RECT  30.996 22.477 31.014 22.981 ;
     RECT  36.36 22.855 41.022 23.017 ;
     RECT  32.544 22.891 35.442 23.053 ;
     RECT  36.324 23.017 41.022 23.053 ;
     RECT  18.615 21.293 18.897 23.089 ;
     RECT  18.615 23.089 18.99 23.161 ;
     RECT  30.78 22.981 31.014 23.161 ;
     RECT  32.544 23.053 41.022 23.161 ;
     RECT  25.38 23.125 25.398 23.279 ;
     RECT  15.912 23.287 15.93 23.323 ;
     RECT  16.848 23.251 16.866 23.323 ;
     RECT  30.78 23.161 41.022 23.323 ;
     RECT  43.092 23.161 43.11 23.323 ;
     RECT  22.824 23.251 22.842 23.351 ;
     RECT  3.96 22.711 3.978 23.395 ;
     RECT  15.912 23.323 16.074 23.395 ;
     RECT  18.324 23.161 18.99 23.395 ;
     RECT  42.156 22.081 42.246 23.405 ;
     RECT  15.876 23.395 16.074 23.521 ;
     RECT  16.848 23.323 17.154 23.521 ;
     RECT  17.964 23.395 18.99 23.521 ;
     RECT  21.024 23.395 21.042 23.521 ;
     RECT  30.636 23.323 41.022 23.549 ;
     RECT  15.876 23.521 17.154 23.557 ;
     RECT  17.964 23.521 19.71 23.557 ;
     RECT  26.424 23.521 26.442 23.557 ;
     RECT  15.624 23.557 19.854 23.621 ;
     RECT  26.424 23.557 26.802 23.621 ;
     RECT  9.252 18.797 9.27 23.629 ;
     RECT  16.848 23.621 19.854 23.657 ;
     RECT  14.868 23.557 14.886 23.665 ;
     RECT  16.884 23.657 19.854 23.665 ;
     RECT  14.832 23.665 14.886 23.666 ;
     RECT  15.624 23.621 15.822 23.693 ;
     RECT  20.952 23.521 21.042 23.693 ;
     RECT  43.056 23.323 43.11 23.693 ;
     RECT  3.96 23.395 4.41 23.701 ;
     RECT  29.415 2.413 29.697 23.701 ;
     RECT  30.636 23.549 32.022 23.701 ;
     RECT  15.732 23.693 15.822 23.729 ;
     RECT  2.415 19.265 2.697 23.791 ;
     RECT  3.528 23.701 4.41 23.791 ;
     RECT  32.76 23.549 41.022 23.791 ;
     RECT  42.156 23.405 42.174 23.791 ;
     RECT  16.884 23.665 20.178 23.819 ;
     RECT  5.184 23.701 5.202 23.855 ;
     RECT  2.415 23.791 4.41 23.863 ;
     RECT  17.028 23.819 20.178 23.899 ;
     RECT  20.952 23.693 20.97 23.899 ;
     RECT  11.736 23.431 11.754 23.935 ;
     RECT  11.736 23.935 12.078 23.971 ;
     RECT  43.092 23.693 43.11 23.981 ;
     RECT  11.736 23.971 12.294 24.061 ;
     RECT  6.768 23.935 6.786 24.089 ;
     RECT  10.944 24.061 12.294 24.089 ;
     RECT  10.944 24.089 12.078 24.125 ;
     RECT  2.415 23.863 4.554 24.205 ;
     RECT  10.944 24.125 12.006 24.205 ;
     RECT  9.252 23.629 9.846 24.241 ;
     RECT  10.764 24.205 12.006 24.241 ;
     RECT  9.252 24.241 12.006 24.331 ;
     RECT  29.415 23.701 32.022 24.331 ;
     RECT  32.76 23.791 42.174 24.331 ;
     RECT  28.368 24.331 28.386 24.431 ;
     RECT  15.732 23.729 15.75 24.475 ;
     RECT  26.784 23.621 26.802 24.503 ;
     RECT  14.832 23.666 14.85 24.511 ;
     RECT  13.215 19.373 13.497 24.601 ;
     RECT  14.616 24.511 14.994 24.601 ;
     RECT  15.732 24.475 16.146 24.601 ;
     RECT  17.028 23.899 20.97 24.601 ;
     RECT  2.304 24.205 4.554 24.629 ;
     RECT  13.215 24.601 13.554 24.709 ;
     RECT  14.616 24.601 16.146 24.709 ;
     RECT  17.028 24.601 21.042 24.737 ;
     RECT  13.215 24.709 16.146 24.811 ;
     RECT  0.108 23.827 0.126 24.859 ;
     RECT  2.304 24.629 4.23 24.859 ;
     RECT  5.004 24.709 5.202 24.871 ;
     RECT  12.996 24.811 16.146 24.871 ;
     RECT  2.232 24.859 4.23 24.899 ;
     RECT  12.924 24.871 16.146 24.899 ;
     RECT  17.028 24.737 20.322 24.907 ;
     RECT  12.924 24.899 15.822 24.943 ;
     RECT  2.232 24.899 2.934 24.971 ;
     RECT  7.815 18.959 8.097 25.015 ;
     RECT  9.144 24.331 12.006 25.015 ;
     RECT  0.108 24.859 0.162 25.051 ;
     RECT  16.596 24.907 20.322 25.079 ;
     RECT  0.108 25.051 0.558 25.133 ;
     RECT  7.815 25.015 12.006 25.141 ;
     RECT  12.852 24.943 15.822 25.241 ;
     RECT  7.164 25.141 12.114 25.243 ;
     RECT  12.852 25.241 14.742 25.243 ;
     RECT  7.164 25.243 14.742 25.249 ;
     RECT  6.804 25.249 14.742 25.285 ;
     RECT  29.415 24.331 42.174 25.349 ;
     RECT  0.108 25.133 0.162 25.421 ;
     RECT  5.004 24.871 5.274 25.439 ;
     RECT  26.784 25.321 26.802 25.555 ;
     RECT  3.708 24.899 4.23 25.579 ;
     RECT  18.615 25.079 20.322 25.583 ;
     RECT  6.768 25.285 14.742 25.591 ;
     RECT  15.516 25.241 15.822 25.681 ;
     RECT  16.596 25.079 17.874 25.681 ;
     RECT  6.228 25.591 14.742 25.709 ;
     RECT  26.748 25.555 26.802 25.709 ;
     RECT  2.304 24.971 2.934 25.717 ;
     RECT  3.708 25.579 4.446 25.717 ;
     RECT  5.184 25.439 5.274 25.717 ;
     RECT  6.804 25.709 6.822 25.781 ;
     RECT  22.824 25.681 22.842 25.781 ;
     RECT  2.304 25.717 4.446 25.817 ;
     RECT  15.516 25.681 17.874 25.817 ;
     RECT  0.144 25.421 0.162 25.853 ;
     RECT  20.7 25.753 21.042 25.853 ;
     RECT  26.784 25.709 26.802 25.861 ;
     RECT  5.184 25.717 5.454 25.951 ;
     RECT  16.848 25.817 17.874 25.951 ;
     RECT  18.615 25.583 19.926 25.951 ;
     RECT  7.812 25.709 14.742 25.979 ;
     RECT  41.58 25.349 42.174 25.979 ;
     RECT  16.848 25.951 19.926 25.997 ;
     RECT  16.848 25.997 17.802 26.015 ;
     RECT  18.615 25.997 19.926 26.015 ;
     RECT  26.784 25.861 26.874 26.023 ;
     RECT  16.848 26.015 17.046 26.051 ;
     RECT  43.092 25.867 43.11 26.059 ;
     RECT  0.324 25.963 0.342 26.093 ;
     RECT  43.092 26.059 43.182 26.093 ;
     RECT  10.584 25.979 14.742 26.131 ;
     RECT  7.812 25.979 9.342 26.159 ;
     RECT  20.7 25.853 20.97 26.159 ;
     RECT  26.784 26.023 26.946 26.159 ;
     RECT  41.832 25.979 42.174 26.249 ;
     RECT  10.584 26.131 14.778 26.257 ;
     RECT  15.516 25.817 16.038 26.257 ;
     RECT  18.615 26.015 19.854 26.285 ;
     RECT  29.415 25.349 40.842 26.321 ;
     RECT  20.844 26.159 20.862 26.357 ;
     RECT  26.856 26.159 26.874 26.393 ;
     RECT  29.415 26.321 31.374 26.393 ;
     RECT  41.832 26.249 41.85 26.429 ;
     RECT  7.815 26.159 9.342 26.519 ;
     RECT  32.22 26.321 40.842 26.519 ;
     RECT  10.584 26.257 16.038 26.525 ;
     RECT  2.304 25.817 4.338 26.539 ;
     RECT  9.144 26.519 9.342 26.555 ;
     RECT  10.584 26.525 15.786 26.555 ;
     RECT  37.188 26.519 40.842 26.555 ;
     RECT  10.584 26.555 14.814 26.591 ;
     RECT  11.844 26.591 14.814 26.627 ;
     RECT  15.66 26.555 15.678 26.627 ;
     RECT  32.22 26.519 36.414 26.627 ;
     RECT  7.815 26.519 8.19 26.663 ;
     RECT  11.844 26.627 14.022 26.663 ;
     RECT  5.184 25.951 5.526 26.671 ;
     RECT  2.196 26.539 4.338 26.699 ;
     RECT  10.584 26.591 10.746 26.699 ;
     RECT  5.184 26.671 5.598 26.789 ;
     RECT  10.584 26.699 10.674 26.789 ;
     RECT  12.78 26.663 14.022 26.789 ;
     RECT  14.796 26.627 14.814 26.789 ;
     RECT  16.776 26.563 16.794 26.789 ;
     RECT  29.415 26.393 31.158 26.789 ;
     RECT  32.22 26.627 32.382 26.789 ;
     RECT  33.156 26.627 36.414 26.789 ;
     RECT  2.196 26.699 4.266 26.825 ;
     RECT  9.144 26.555 9.162 26.825 ;
     RECT  32.22 26.789 32.238 26.825 ;
     RECT  34.776 26.789 36.234 26.825 ;
     RECT  34.776 26.825 36.018 26.897 ;
     RECT  13.068 26.789 13.497 26.933 ;
     RECT  33.444 26.789 33.678 27.059 ;
     RECT  34.776 26.897 35.442 27.059 ;
     RECT  2.196 26.825 3.87 27.095 ;
     RECT  33.444 27.059 33.534 27.095 ;
     RECT  37.872 26.555 40.842 27.095 ;
     RECT  0.144 26.587 0.162 27.101 ;
     RECT  2.232 27.095 3.87 27.329 ;
     RECT  31.14 26.789 31.158 27.329 ;
     RECT  38.664 27.095 40.842 27.329 ;
     RECT  38.736 27.329 40.842 27.365 ;
     RECT  2.232 27.329 3.078 27.437 ;
     RECT  3.852 27.329 3.87 27.599 ;
     RECT  33.444 27.095 33.462 27.869 ;
     RECT  34.815 27.059 35.442 28.319 ;
     RECT  2.304 27.437 3.078 28.409 ;
     RECT  37.872 27.095 37.89 28.409 ;
     RECT  38.772 27.365 40.842 28.409 ;
     RECT  2.304 28.409 2.697 28.445 ;
     RECT  38.772 28.409 40.734 28.481 ;
     RECT  39.06 28.481 40.734 28.679 ;
     RECT  39.06 28.679 40.662 28.949 ;
     RECT  43.164 26.093 43.182 28.949 ;
     RECT  39.348 28.949 40.662 28.985 ;
     RECT  39.348 28.985 40.497 29.219 ;
     RECT  39.348 29.219 39.366 29.255 ;
     RECT  2.415 28.445 2.697 40.787 ;
     RECT  7.815 26.663 8.097 40.787 ;
     RECT  13.215 26.933 13.497 40.787 ;
     RECT  18.615 26.285 18.897 40.787 ;
     RECT  24.015 21.569 24.297 40.787 ;
     RECT  29.415 26.789 29.697 40.787 ;
     RECT  34.815 28.319 35.097 40.787 ;
     RECT  40.215 29.219 40.497 40.787 ;
     RECT  2.415 40.787 2.505 41.057 ;
     RECT  7.815 40.787 7.905 41.057 ;
     RECT  13.215 40.787 13.305 41.057 ;
     RECT  18.615 40.787 18.705 41.057 ;
     RECT  24.015 40.787 24.105 41.057 ;
     RECT  29.415 40.787 29.505 41.057 ;
     RECT  34.815 40.787 34.905 41.057 ;
     RECT  40.215 40.787 40.305 41.057 ;
    LAYER M4 ;
     RECT  0.06 24.048 0.133 27.048 ;
     RECT  0.133 24.048 0.227 27.096 ;
     RECT  0.06 16.368 2.408 18.6 ;
     RECT  0.181 21.456 2.408 21.48 ;
     RECT  0.227 24.144 2.408 27.096 ;
     RECT  2.408 2.148 2.512 41.052 ;
     RECT  2.512 2.418 2.704 40.782 ;
     RECT  2.704 24.144 2.801 26.664 ;
     RECT  2.704 16.368 2.873 18.504 ;
     RECT  2.801 24.72 4.241 26.664 ;
     RECT  4.241 25.584 4.277 26.664 ;
     RECT  2.873 16.512 4.421 18.504 ;
     RECT  4.277 25.584 4.457 25.992 ;
     RECT  4.421 16.56 5.177 18.504 ;
     RECT  4.457 25.968 5.213 25.992 ;
     RECT  5.177 16.656 5.501 18.456 ;
     RECT  5.501 16.656 5.573 16.872 ;
     RECT  5.573 16.656 5.717 16.824 ;
     RECT  5.501 17.904 5.717 18.456 ;
     RECT  5.717 18.144 6.077 18.456 ;
     RECT  6.077 18.192 6.829 18.456 ;
     RECT  6.829 18.192 6.937 18.792 ;
     RECT  6.757 25.296 7.369 25.32 ;
     RECT  5.717 16.656 7.808 16.68 ;
     RECT  6.937 18.192 7.808 18.84 ;
     RECT  2.704 21.456 7.808 21.48 ;
     RECT  7.369 25.296 7.808 25.464 ;
     RECT  7.808 2.148 7.912 41.052 ;
     RECT  7.912 2.418 8.104 40.782 ;
     RECT  8.104 25.296 9.029 25.752 ;
     RECT  8.104 17.664 9.059 18.84 ;
     RECT  9.059 17.664 9.1 18.216 ;
     RECT  9.029 25.296 9.133 25.704 ;
     RECT  9.133 25.104 9.493 25.704 ;
     RECT  9.1 17.664 9.529 18.168 ;
     RECT  9.493 24.24 9.677 25.704 ;
     RECT  9.529 16.8 9.709 18.168 ;
     RECT  9.709 16.272 10.145 18.168 ;
     RECT  10.145 16.272 10.505 17.976 ;
     RECT  9.677 24.24 10.753 24.264 ;
     RECT  9.677 25.296 10.753 25.704 ;
     RECT  10.753 24.24 10.793 25.704 ;
     RECT  10.793 24.816 11.617 25.704 ;
     RECT  11.617 24.816 11.761 26.088 ;
     RECT  10.505 16.992 12.733 17.976 ;
     RECT  11.761 24.816 12.997 26.328 ;
     RECT  12.733 16.992 13.093 18.024 ;
     RECT  13.093 16.656 13.208 18.024 ;
     RECT  12.769 19.344 13.208 19.368 ;
     RECT  8.104 21.456 13.208 21.48 ;
     RECT  12.997 24.816 13.208 26.904 ;
     RECT  13.208 2.148 13.312 41.052 ;
     RECT  13.312 2.418 13.504 40.782 ;
     RECT  13.504 17.424 14.393 19.368 ;
     RECT  13.504 24.96 14.569 25.752 ;
     RECT  14.393 17.712 14.717 19.368 ;
     RECT  14.569 16.416 14.773 16.44 ;
     RECT  14.773 16.416 14.819 16.68 ;
     RECT  14.569 24.96 14.821 26.328 ;
     RECT  14.819 16.56 14.933 16.68 ;
     RECT  14.717 17.904 15.469 19.368 ;
     RECT  14.821 24.624 15.649 26.328 ;
     RECT  15.469 17.904 15.797 19.656 ;
     RECT  13.504 21.456 15.925 21.48 ;
     RECT  15.797 18.144 15.971 19.656 ;
     RECT  15.649 24.624 16.049 26.52 ;
     RECT  16.049 24.624 16.117 25.656 ;
     RECT  15.901 23.328 17.165 23.352 ;
     RECT  16.117 24.48 17.237 25.656 ;
     RECT  15.971 18.144 18.608 18.744 ;
     RECT  15.925 21.216 18.608 21.48 ;
     RECT  17.237 24.48 18.608 24.648 ;
     RECT  17.629 25.776 18.608 25.992 ;
     RECT  18.608 2.148 18.712 41.052 ;
     RECT  18.712 2.418 18.904 40.782 ;
     RECT  18.904 24.48 19.361 25.8 ;
     RECT  19.361 24.48 19.973 25.32 ;
     RECT  18.904 17.904 20.009 17.928 ;
     RECT  19.973 25.296 20.333 25.32 ;
     RECT  18.904 21.264 24.008 21.48 ;
     RECT  24.008 2.148 24.112 41.052 ;
     RECT  24.112 2.418 24.304 40.782 ;
     RECT  24.304 21.456 29.408 21.48 ;
     RECT  29.408 2.148 29.512 41.052 ;
     RECT  29.512 2.418 29.704 40.782 ;
     RECT  29.704 23.376 30.593 24.696 ;
     RECT  30.593 24.48 30.805 24.696 ;
     RECT  29.704 25.776 30.805 26.328 ;
     RECT  30.593 23.376 30.851 23.4 ;
     RECT  30.805 24.48 30.881 26.328 ;
     RECT  30.881 24.48 31.313 25.848 ;
     RECT  32.165 26.784 32.249 26.808 ;
     RECT  31.633 19.104 32.461 19.128 ;
     RECT  31.313 24.48 32.461 25.704 ;
     RECT  32.461 18.192 33.001 19.128 ;
     RECT  32.677 16.032 33.037 16.056 ;
     RECT  32.461 24.336 33.107 25.704 ;
     RECT  33.107 24.336 33.469 25.464 ;
     RECT  33.469 24.288 33.689 25.464 ;
     RECT  33.001 18.192 33.757 19.416 ;
     RECT  33.689 24.288 33.781 25.416 ;
     RECT  33.037 16.032 33.925 16.344 ;
     RECT  33.925 16.032 34.765 16.584 ;
     RECT  34.765 16.032 34.808 17.112 ;
     RECT  33.757 18.192 34.808 19.896 ;
     RECT  29.704 21.456 34.808 21.48 ;
     RECT  33.781 23.904 34.808 25.416 ;
     RECT  33.505 26.784 34.808 26.808 ;
     RECT  34.808 2.148 34.912 41.052 ;
     RECT  34.912 2.418 35.104 40.782 ;
     RECT  35.104 23.808 35.309 26.28 ;
     RECT  35.104 16.032 35.525 18.84 ;
     RECT  35.525 16.032 36.029 18.792 ;
     RECT  36.029 16.032 36.065 16.632 ;
     RECT  35.309 26.256 36.101 26.28 ;
     RECT  35.309 23.808 36.389 25.08 ;
     RECT  36.029 18 36.497 18.792 ;
     RECT  36.389 23.808 36.569 24.456 ;
     RECT  36.569 23.808 36.601 24.216 ;
     RECT  36.065 16.032 36.677 16.392 ;
     RECT  36.677 16.368 36.785 16.392 ;
     RECT  36.601 23.664 37.037 24.216 ;
     RECT  37.141 26.064 37.177 26.088 ;
     RECT  36.497 18.192 37.321 18.792 ;
     RECT  37.177 26.064 37.357 26.28 ;
     RECT  37.321 18.192 37.433 19.08 ;
     RECT  37.037 23.808 37.717 24.216 ;
     RECT  37.357 25.632 37.717 26.28 ;
     RECT  37.393 17.088 37.789 17.112 ;
     RECT  37.717 23.808 37.909 26.28 ;
     RECT  37.433 19.056 38.117 19.08 ;
     RECT  37.789 16.896 38.225 17.112 ;
     RECT  37.909 23.808 38.369 26.76 ;
     RECT  38.369 23.808 38.389 24.744 ;
     RECT  38.389 23.328 38.435 24.744 ;
     RECT  38.225 16.896 38.549 16.92 ;
     RECT  38.435 23.328 38.549 23.352 ;
     RECT  38.369 26.256 38.621 26.76 ;
     RECT  38.435 24.72 38.765 24.744 ;
     RECT  38.621 26.736 38.945 26.76 ;
     RECT  40.021 16.656 40.208 16.68 ;
     RECT  40.208 2.148 40.312 41.052 ;
     RECT  40.312 2.418 40.504 40.782 ;
     RECT  40.504 25.968 40.853 26.808 ;
     RECT  40.504 22.992 41.533 24.648 ;
     RECT  40.853 25.968 41.533 25.992 ;
     RECT  41.533 22.992 43.081 25.992 ;
     RECT  40.504 16.176 43.164 18.312 ;
     RECT  43.081 22.992 43.164 26.088 ;
     RECT  43.164 26.064 43.193 26.088 ;
    LAYER M5 ;
     RECT  2.4 2.137 2.52 2.151 ;
     RECT  7.8 2.137 7.92 2.151 ;
     RECT  13.2 2.137 13.32 2.151 ;
     RECT  18.6 2.137 18.72 2.151 ;
     RECT  24 2.137 24.12 2.151 ;
     RECT  29.4 2.137 29.52 2.151 ;
     RECT  34.8 2.137 34.92 2.151 ;
     RECT  40.2 2.137 40.32 2.151 ;
     RECT  34.8 2.151 35.112 16.069 ;
     RECT  13.2 2.151 13.512 16.645 ;
     RECT  33.936 16.069 35.112 17.077 ;
     RECT  13.104 16.645 13.512 17.651 ;
     RECT  33.936 17.077 35.448 18.131 ;
     RECT  14.784 16.405 14.808 18.179 ;
     RECT  7.8 2.151 8.112 18.181 ;
     RECT  37.056 18.181 37.08 18.467 ;
     RECT  7.8 18.181 9.048 18.851 ;
     RECT  33.936 18.131 35.4 18.851 ;
     RECT  33.936 18.851 35.112 19.861 ;
     RECT  33.888 19.861 35.112 23.893 ;
     RECT  33.792 23.893 35.112 23.939 ;
     RECT  0.192 21.445 0.216 24.083 ;
     RECT  18.6 2.151 18.912 24.469 ;
     RECT  38.4 23.317 38.424 24.659 ;
     RECT  33.792 23.939 33.816 25.045 ;
     RECT  18.6 24.469 19.32 25.139 ;
     RECT  33.072 25.045 33.816 25.187 ;
     RECT  15.936 19.621 15.96 25.283 ;
     RECT  0.144 24.949 0.168 25.477 ;
     RECT  34.8 23.939 35.112 25.621 ;
     RECT  33.072 25.187 33.096 25.669 ;
     RECT  0.144 25.477 0.312 25.715 ;
     RECT  32.208 25.669 33.096 25.715 ;
     RECT  13.2 17.651 13.512 25.717 ;
     RECT  30.816 23.365 30.84 26.147 ;
     RECT  0.144 25.715 0.168 26.243 ;
     RECT  37.584 25.621 37.608 26.245 ;
     RECT  34.8 25.621 35.208 26.291 ;
     RECT  37.584 26.245 37.944 26.291 ;
     RECT  37.92 26.291 37.944 26.771 ;
     RECT  32.208 25.715 32.232 26.819 ;
     RECT  13.008 25.717 13.512 26.915 ;
     RECT  2.4 2.151 2.712 41.049 ;
     RECT  7.8 18.851 8.112 41.049 ;
     RECT  13.2 26.915 13.512 41.049 ;
     RECT  18.6 25.139 18.912 41.049 ;
     RECT  24 2.151 24.312 41.049 ;
     RECT  29.4 2.151 29.712 41.049 ;
     RECT  34.8 26.291 35.112 41.049 ;
     RECT  40.2 2.151 40.512 41.049 ;
     RECT  2.4 41.049 2.52 41.063 ;
     RECT  7.8 41.049 7.92 41.063 ;
     RECT  13.2 41.049 13.32 41.063 ;
     RECT  18.6 41.049 18.72 41.063 ;
     RECT  24 41.049 24.12 41.063 ;
     RECT  29.4 41.049 29.52 41.063 ;
     RECT  34.8 41.049 34.92 41.063 ;
     RECT  40.2 41.049 40.32 41.063 ;
     RECT  13.512 16.405 14.784 18.179 ;
     RECT  29.712 23.365 30.816 26.147 ;
     RECT  33.816 23.939 34.8 25.187 ;
     RECT  0.192 24.083 0.216 24.949 ;
     RECT  0.168 24.949 0.216 25.477 ;
     RECT  30.84 25.669 32.208 26.147 ;
  END
END ot_hgi_sm_pub_egress
END LIBRARY
